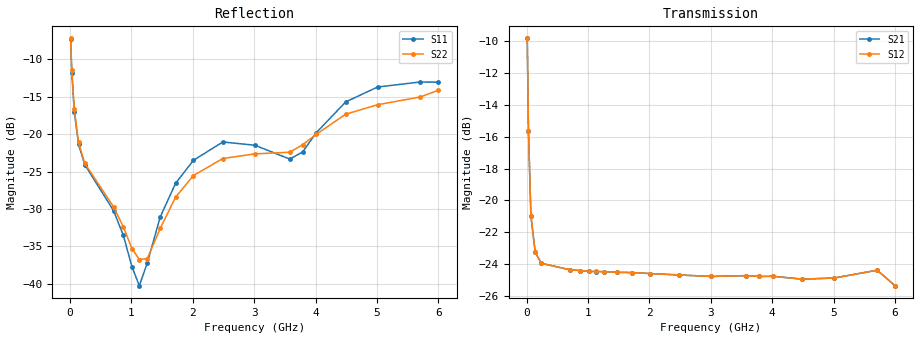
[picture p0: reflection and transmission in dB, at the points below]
! Integrated Device Technology
! Corporate Headquarters
! 6024 Silver Creek Valley Road
! San Jose, CA 95138  USA
! Phone:  1-408-284-8200
! Toll Free:  1-800-223-1366
! Webpage:  http://www.idt.com/
! Timing and RF Division
! 515 Groton Road, Suite 102
! Westford, MA 01886-6024
! Device:  F1951
! Description: 6-bit 0.5 dB Digital Step Attenuator
! Frequency:  100.0 -  4000.00 MHz
! Package:  4x4 mm Thin QFN Plastic Package: 24 pin
! Ports:  2 RF, 6 DC
!  Pin  1  = NC
!  Pin  2  = RF1  =  Port 1
!  Pin  3  = GND
!  Pin  4  = NC
!  Pin  5  = Serial Data Out (SDO)
!  Pin  6  = NC
!  Pin  7  = Reset Bar ( RSTb)
!  Pin  8  = Clock (CLK)
!  Pin  9  = Chip Select Bar (CSb)
!  Pin 10  = NC
!  Pin 11  = Serial Data In (SDI)
!  Pin 12  = NC
!  Pin 13  = NC
!  Pin 14  = VDD
!  Pin 15  = NC
!  Pin 16  = GND
!  Pin 17  = RF2  =  Port 2
!  Pin 18  = NC
!  Pin 19  = GND
!  Pin 20  = GND
!  Pin 21  = GND
!  Pin 22  = GND
!  Pin 23  = GND
!  Pin 24  = GND
! State:  47
! Atten State:  23.5 dB
! Voltage:  +3.30 Volts
! Current:  0.484 mA
! Data:  The device was measured on a F195X evaluation board which has
!  individual transmission lines to the RF pins.  Data was collected
!  de-embedded using a Automatic Fixture Removal [AFR] (Keysight Technologies).
!  The reference plane is the edge of the package pin.
! Misc:  Lot Code  1225BCA
!  Action Tracker AT0399
! Date Measured:  2018-09-13
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# GHz S dB R 50
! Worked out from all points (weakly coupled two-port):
!   600 points, 10 MHz to 6 GHz, reference 50 ohm
!   highest |S21| = -9.84 dB at 10 MHz (marker M1); lowest = -25.3 dB at 6 GHz (marker M2)
!   lowest |S11| = -40.3 dB at 1.13 GHz (marker M3), VSWR 1.02, Z = 49.1 + j0.171 ohm
!   |S11| at or under -10 dB: 20.93 MHz to end of sweep
!   |S22| runs from -37.2 to -7.2 dB; largest |S21 - S12| = 0.00017
!   S11 on the Smith chart (normalised r, x): 10 MHz: 1.72, -1.02; 30 MHz: 1.13, -0.55; 70 MHz: 0.98, -0.28; 1.47 GHz: 0.98, +0.05; 6 GHz: 0.81, +0.36
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0.01  -7.34 -34.2  -9.84 -33.9  -9.84 -33.9  -7.19 -32.5
0.03  -11.80 -62.1  -15.65 -50.1  -15.65 -50.1  -11.38 -60.9
0.07  -16.98 -86.6  -20.97 -41.4  -20.97 -41.4  -16.60 -86.3
0.14  -21.38 -107.6  -23.25 -26.9  -23.25 -26.8  -21.08 -106.9
0.24  -24.07 -121.9  -23.94 -18.8  -23.94 -18.7  -23.90 -121.6
0.71  -30.23 -133.2  -24.35 -15.2  -24.34 -15.2  -29.72 -137.0
0.87  -33.55 -137.5  -24.39 -16.4  -24.39 -16.5  -32.43 -141.7
1.01  -37.75 -152.5  -24.44 -17.6  -24.44 -17.6  -35.30 -151.3
1.13  -40.27 169.6  -24.46 -18.6  -24.45 -18.6  -36.77 -170.0
1.26  -37.22 129.0  -24.46 -20.0  -24.46 -20.0  -36.64 163.2
1.47  -31.08 113.8  -24.50 -22.4  -24.50 -22.4  -32.61 140.9
1.72  -26.59 115.0  -24.52 -25.3  -24.52 -25.3  -28.44 131.0
2.01  -23.51 122.4  -24.58 -28.9  -24.58 -28.9  -25.55 133.5
2.49  -21.05 135.8  -24.67 -34.7  -24.67 -34.7  -23.26 141.1
3.01  -21.48 146.1  -24.76 -40.8  -24.76 -40.8  -22.64 144.7
3.58  -23.33 124.3  -24.71 -47.4  -24.71 -47.4  -22.42 127.1
3.79  -22.39 108.3  -24.76 -49.9  -24.76 -49.9  -21.42 120.2
4.01  -19.83 99.9  -24.75 -52.5  -24.75 -52.5  -20.04 115.0
4.49  -15.70 98.5  -24.93 -57.8  -24.93 -57.7  -17.34 113.4
5.01  -13.70 107.6  -24.86 -61.5  -24.86 -61.5  -16.07 116.2
5.71  -13.02 112.8  -24.37 -72.8  -24.37 -72.7  -15.02 109.4
6  -13.06 106.6  -25.34 -76.0  -25.33 -76.0  -14.13 105.7
